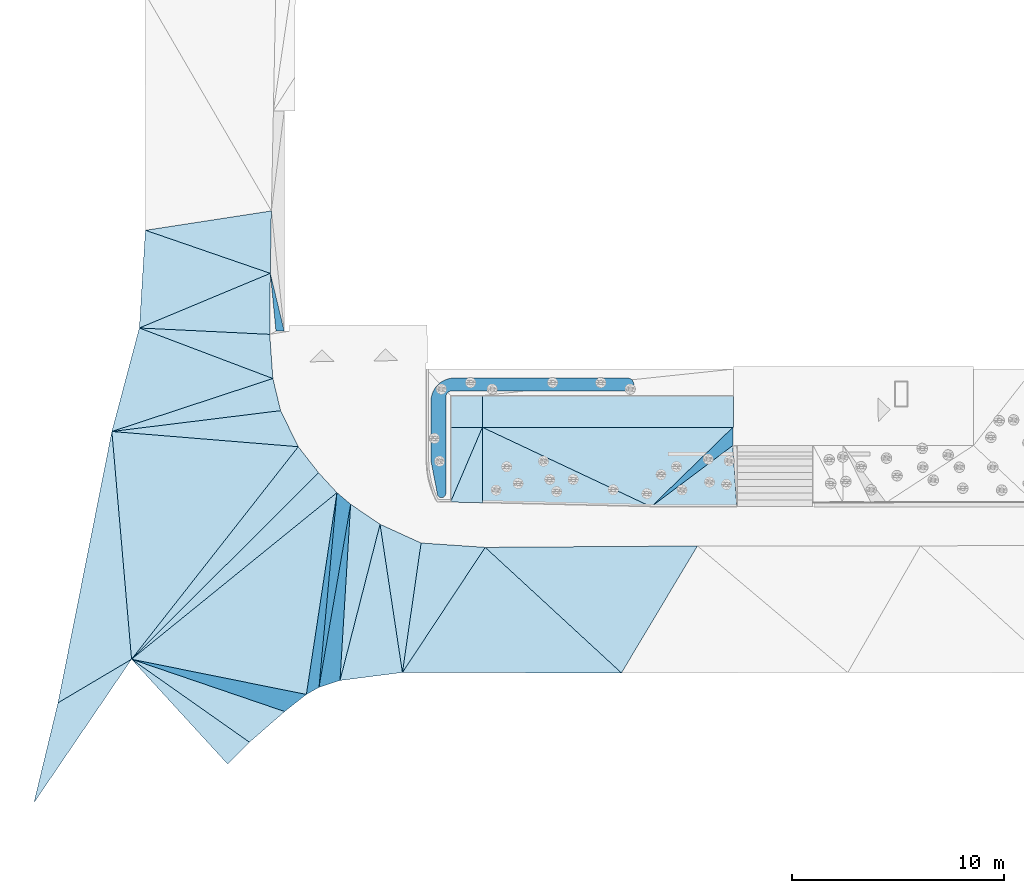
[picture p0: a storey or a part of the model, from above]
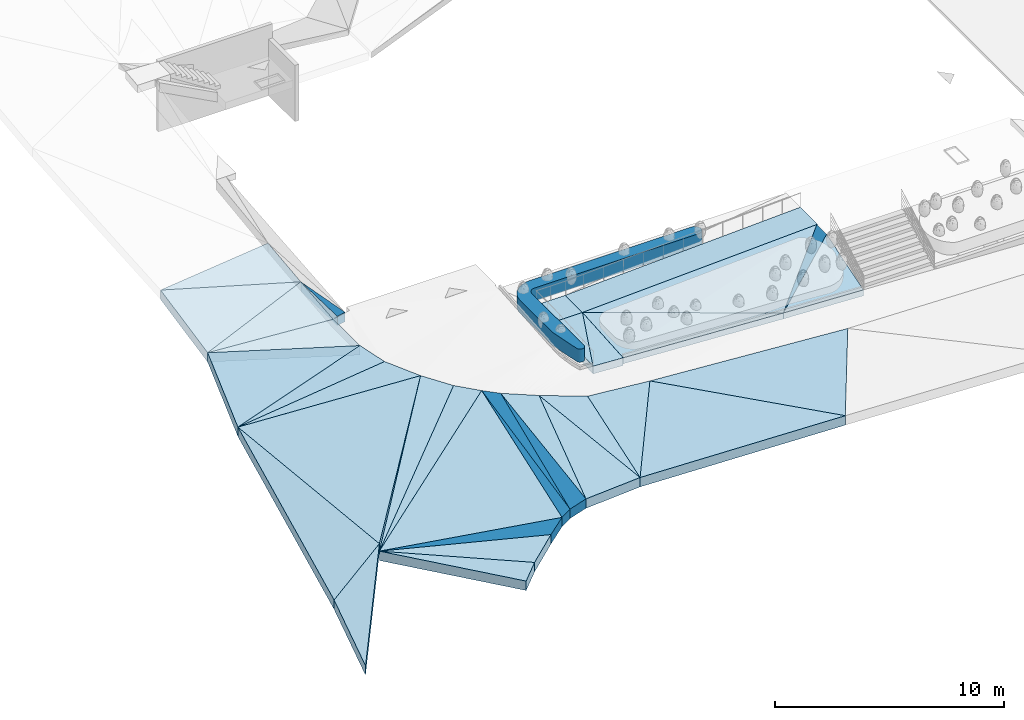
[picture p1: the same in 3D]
Properties of the parts of a building model (IFC2X3), part 1 of 2

# File
Description: ViewDefinition [CoordinationView_V2.0], RevitIdentifiers [ContentGUID: , VersionGUID: e908e2d4-4760-4d74-834a-3a2befb9f71d, NumberOfSaves: 164], ExchangeRequirement [], CoordinateReference [CoordinateBase: Project Base Point, ProjectSite: Internal]
File name: A246760_Ombygging av eksisterende legevakt_LARK.ifc
Time: 2025-12-17T15:13:17+01:00
Organization: Arkitema
Written by: ODA SDAI 22.12
Made in: Autodesk Revit 23.1.80.30 (ENU) - IFC 23.4.1.0

# IfcProject, A236760
LongName: TROMSØ LEGEVAKT; Phase: <Project Status>

# IfcSite, Default
RefLatitude: 59, 54, 57, 601318; RefLongitude: 10, 44, 59, 999999; RefElevation: 0 m

# IfcSite: Coordinate Marker Primary:Landscape Architect, Coordinate Marker Primary:Landscape Architect:896850
Material: A_Coordinate Marker_URB

# IfcBuilding, <Building Name>
LongName: <Building Name>
Pset_BuildingCommon - NumberOfStoreys: 1

# IfcBuildingStorey: Level:A_Level_Project Base Point, 00 - HAV
In: <Building Name>
LongName: 00 - HAV; Elevation: 0 m
Pset_AirSideSystemInformation - Name: 00 - HAV; sets with these values: 2

# IfcBuildingElementProxy: 011_Entrépil_3D:Hovedentré (6)
In: 00 - HAV
Type - Material: Entrépil
Pset_BuildingElementProxyCommon - Reference: Hovedentré; sets with these values: 2
Name (011_Entrépil_3D:Hovedentré:...)
1719524
1719576
1719661
1719735
1926711
1976187

# IfcBuildingElementProxy: 812_Shrub_Solitary:812xxx Amelanchier laevis (Allegheny serviceberry) (Multi-stem), 4m 2 (49)
In: 00 - HAV
Type - Material: <Unnamed>
Classification: 812 (Uniformat)
Pset_BuildingElementProxyCommon - Reference: 812xxx Amelanchier laevis (Allegheny serviceberry) (Multi-stem), 4m 2; sets with these values: 2
Name (812_Shrub_Solitary:812xxx Amelanchier laevis (Allegheny serviceberry) (Multi-stem), 4m 2:...)
1756752
1756895
1757022
1757053
1757088
1757123
1757158
1757193
1757228
1757263
1757323
1757370
1757407
1757446
1757481
1757514
1757553
1757588
1757623
1757658
1757697
1757736
1757783
1757818
1757865
1757928
1757989
1758052
1758127
1758190
1758253
1758316
1758377
1758440
1758503
1758564
1758690
1952593
1952684
1952703
1952741
1960945
1960970
1960990
1961012
1961034
1961054
1961074
1961094

# IfcBuildingElementProxy: rist:rist (3)
In: 00 - HAV
Type - Material: A_Default_Building_Component
Pset_BuildingElementProxyCommon - Reference: rist; sets with these values: 2
Name (rist:rist:...)
1971097
1971388
1971627

# IfcRailing: Railing:760 Kantstein 120x300mm (5)
In: 00 - HAV
Classification: 76 Veger og plasser (Uniformat)
Pset_QuantityTakeOff - Reference: 760 Kantstein 120x300mm
Pset_RailingCommon - IsExternal: no; Reference: 760 Kantstein 120x300mm; Height: 1.2 m
Name (Railing:760 Kantstein 120x300mm:...) | Material
1765355 | Site - Concrete - Curb
1765792 | Site - Concrete - Curb
1766145 | Site - Concrete - Curb, A_Default_Building_Part
1979676 | Site - Concrete - Curb
1979781 | Site - Concrete - Curb

# IfcRailing: Railing:800mm Pipe håndløper, Railing:800mm Pipe håndløper:1772769
In: 00 - HAV
Material: A_Finish_Metal_Steel_Brushed, Lys
Pset_QuantityTakeOff - Reference: 800mm Pipe håndløper
Pset_RailingCommon - IsExternal: no; Reference: 800mm Pipe håndløper; Height: 1.2192 m

# IfcRailing: Railing:900mm Pipe (2)
In: 00 - HAV
Material: A_Finish_Metal_Steel_Brushed, Lys
Pset_QuantityTakeOff - Reference: 900mm Pipe
Pset_RailingCommon - IsExternal: no; Reference: 900mm Pipe; Height: 1.2192 m
Name (Railing:900mm Pipe:...)
1718188
1718577

# IfcRoof: Basic Roof:772 Stauder, Geranium phaeum (Storkenæb Bølgekronede) (4)
In: 00 - HAV
Classification: 772 Beplantning (Uniformat); Material: Planting - Shrubs and hedges - Busker 0.7 m
Pset_QuantityTakeOff - Reference: 772 Stauder, Geranium phaeum (Storkenæb Bølgekronede)
Pset_RoofCommon - IsExternal: yes; Reference: 772 Stauder, Geranium phaeum (Storkenæb Bølgekronede)
Name (Basic Roof:772 Stauder, Geranium phaeum (Storkenæb Bølgekronede):...) | ProjectedArea (m2) | TotalArea (m2)
1930701 | 30.0611 | 30.9692
1931496 | 27.967 | 29.6557
1931990 | 4.85519 | 4.55826
1960116 | 8.22603 | 8.65733

# IfcSlab: Basic Roof:772 Stauder, Geranium phaeum (Storkenæb Bølgekronede) (2)
In: 00 - HAV
PredefinedType: ROOF; Classification: 772 Beplantning (Uniformat); Material: Planting - Shrubs and hedges - Busker 0.7 m
Pset_QuantityTakeOff - Reference: 772 Stauder, Geranium phaeum (Storkenæb Bølgekronede); sets with these values: 2
Pset_SlabCommon - IsExternal: yes; PitchAngle: 0 deg; Reference: 772 Stauder, Geranium phaeum (Storkenæb Bølgekronede)
Name (Basic Roof:772 Stauder, Geranium phaeum (Storkenæb Bølgekronede):...)
1931990
1960116

# IfcSlab: Floor:760 Grus, Floor:760 Grus:1980512
In: 00 - HAV
Type - PredefinedType: FLOOR
Classification: 76 Veger og plasser (Uniformat); Material: Site - Gravel - Steinmel, Site - Gravel - Stabilitet grus, Site - Gravel - Bunnsikringsgrus
Pset_QuantityTakeOff - Reference: 760 Grus; sets with these values: 2
Pset_SlabCommon - IsExternal: yes; LoadBearing: no; Reference: 760 Grus; PitchAngle: 27.9591 deg

# IfcSlab: Floor:761 Asfalt - Gangarealer (77)
In: 00 - HAV
Classification: 761 Veger (Uniformat)
Pset_QuantityTakeOff - Reference: 761 Asfalt - Gangarealer; sets with these values: 2
Pset_SlabCommon - IsExternal: yes; LoadBearing: no; Reference: 761 Asfalt - Gangarealer
Name (Floor:761 Asfalt - Gangarealer:...) | PitchAngle (deg) | Material
1763140 | 3.70708
3 x 1763140 | 3.70708 | Site - Aspahlt - Pulverasfalt 0.025 m, A_Default_Building_Part 0.05 m, Site - Gravel - Stabilitet grus 0.1 m, Site - Gravel - Bunnsikringsgrus 0.325 m
1763140 | 2.22173 | Site - Aspahlt - Pulverasfalt 0.025 m, A_Default_Building_Part 0.05 m, Site - Gravel - Stabilitet grus 0.1 m, Site - Gravel - Bunnsikringsgrus 0.325 m
1763140 | 1.93982 | Site - Aspahlt - Pulverasfalt 0.025 m, A_Default_Building_Part 0.05 m, Site - Gravel - Stabilitet grus 0.1 m, Site - Gravel - Bunnsikringsgrus 0.325 m
1763140 | 3.72437 | Site - Aspahlt - Pulverasfalt 0.025 m, A_Default_Building_Part 0.05 m, Site - Gravel - Stabilitet grus 0.1 m, Site - Gravel - Bunnsikringsgrus 0.325 m
1763140 | 0.475138 | Site - Aspahlt - Pulverasfalt 0.025 m, A_Default_Building_Part 0.05 m, Site - Gravel - Stabilitet grus 0.1 m, Site - Gravel - Bunnsikringsgrus 0.325 m
1763140 | 2.44105 | Site - Aspahlt - Pulverasfalt 0.025 m, A_Default_Building_Part 0.05 m, Site - Gravel - Stabilitet grus 0.1 m, Site - Gravel - Bunnsikringsgrus 0.325 m
1763140 | 3.73939 | Site - Aspahlt - Pulverasfalt 0.025 m, A_Default_Building_Part 0.05 m, Site - Gravel - Stabilitet grus 0.1 m, Site - Gravel - Bunnsikringsgrus 0.325 m
1763140 | 0.317033 | Site - Aspahlt - Pulverasfalt 0.025 m, A_Default_Building_Part 0.05 m, Site - Gravel - Stabilitet grus 0.1 m, Site - Gravel - Bunnsikringsgrus 0.325 m
1763140 | 0.778442 | Site - Aspahlt - Pulverasfalt 0.025 m, A_Default_Building_Part 0.05 m, Site - Gravel - Stabilitet grus 0.1 m, Site - Gravel - Bunnsikringsgrus 0.325 m
1763140 | 0.641729 | Site - Aspahlt - Pulverasfalt 0.025 m, A_Default_Building_Part 0.05 m, Site - Gravel - Stabilitet grus 0.1 m, Site - Gravel - Bunnsikringsgrus 0.325 m
1763140 | 2.55907 | Site - Aspahlt - Pulverasfalt 0.025 m, A_Default_Building_Part 0.05 m, Site - Gravel - Stabilitet grus 0.1 m, Site - Gravel - Bunnsikringsgrus 0.325 m
1763140 | 2.20551 | Site - Aspahlt - Pulverasfalt 0.025 m, A_Default_Building_Part 0.05 m, Site - Gravel - Stabilitet grus 0.1 m, Site - Gravel - Bunnsikringsgrus 0.325 m
1763140 | 1.61241 | Site - Aspahlt - Pulverasfalt 0.025 m, A_Default_Building_Part 0.05 m, Site - Gravel - Stabilitet grus 0.1 m, Site - Gravel - Bunnsikringsgrus 0.325 m
1763140 | 3.23586 | Site - Aspahlt - Pulverasfalt 0.025 m, A_Default_Building_Part 0.05 m, Site - Gravel - Stabilitet grus 0.1 m, Site - Gravel - Bunnsikringsgrus 0.325 m
1763140 | 2.4268 | Site - Aspahlt - Pulverasfalt 0.025 m, A_Default_Building_Part 0.05 m, Site - Gravel - Stabilitet grus 0.1 m, Site - Gravel - Bunnsikringsgrus 0.325 m
1763140 | 2.91863 | Site - Aspahlt - Pulverasfalt 0.025 m, A_Default_Building_Part 0.05 m, Site - Gravel - Stabilitet grus 0.1 m, Site - Gravel - Bunnsikringsgrus 0.325 m
1763140 | 3.35113 | Site - Aspahlt - Pulverasfalt 0.025 m, A_Default_Building_Part 0.05 m, Site - Gravel - Stabilitet grus 0.1 m, Site - Gravel - Bunnsikringsgrus 0.325 m
1763140 | 2.57261 | Site - Aspahlt - Pulverasfalt 0.025 m, A_Default_Building_Part 0.05 m, Site - Gravel - Stabilitet grus 0.1 m, Site - Gravel - Bunnsikringsgrus 0.325 m
1763140 | 2.5678 | Site - Aspahlt - Pulverasfalt 0.025 m, A_Default_Building_Part 0.05 m, Site - Gravel - Stabilitet grus 0.1 m, Site - Gravel - Bunnsikringsgrus 0.325 m
1763140 | 3.9037 | Site - Aspahlt - Pulverasfalt 0.025 m, A_Default_Building_Part 0.05 m, Site - Gravel - Stabilitet grus 0.1 m, Site - Gravel - Bunnsikringsgrus 0.325 m
1763140 | 2.61773 | Site - Aspahlt - Pulverasfalt 0.025 m, A_Default_Building_Part 0.05 m, Site - Gravel - Stabilitet grus 0.1 m, Site - Gravel - Bunnsikringsgrus 0.325 m
1763140 | 1.37486 | Site - Aspahlt - Pulverasfalt 0.025 m, A_Default_Building_Part 0.05 m, Site - Gravel - Stabilitet grus 0.1 m, Site - Gravel - Bunnsikringsgrus 0.325 m
1763140 | 4.61341 | Site - Aspahlt - Pulverasfalt 0.025 m, A_Default_Building_Part 0.05 m, Site - Gravel - Stabilitet grus 0.1 m, Site - Gravel - Bunnsikringsgrus 0.325 m
1763140 | 5.71507 | Site - Aspahlt - Pulverasfalt 0.025 m, A_Default_Building_Part 0.05 m, Site - Gravel - Stabilitet grus 0.1 m, Site - Gravel - Bunnsikringsgrus 0.325 m
1763140 | 5.27475 | Site - Aspahlt - Pulverasfalt 0.025 m, A_Default_Building_Part 0.05 m, Site - Gravel - Stabilitet grus 0.1 m, Site - Gravel - Bunnsikringsgrus 0.325 m
1763140 | 4.27942 | Site - Aspahlt - Pulverasfalt 0.025 m, A_Default_Building_Part 0.05 m, Site - Gravel - Stabilitet grus 0.1 m, Site - Gravel - Bunnsikringsgrus 0.325 m
1763140 | 3.64257 | Site - Aspahlt - Pulverasfalt 0.025 m, A_Default_Building_Part 0.05 m, Site - Gravel - Stabilitet grus 0.1 m, Site - Gravel - Bunnsikringsgrus 0.325 m
1763140 | 3.82142 | Site - Aspahlt - Pulverasfalt 0.025 m, A_Default_Building_Part 0.05 m, Site - Gravel - Stabilitet grus 0.1 m, Site - Gravel - Bunnsikringsgrus 0.325 m
1763140 | 3.6637 | Site - Aspahlt - Pulverasfalt 0.025 m, A_Default_Building_Part 0.05 m, Site - Gravel - Stabilitet grus 0.1 m, Site - Gravel - Bunnsikringsgrus 0.325 m
1763140 | 5.95443 | Site - Aspahlt - Pulverasfalt 0.025 m, A_Default_Building_Part 0.05 m, Site - Gravel - Stabilitet grus 0.1 m, Site - Gravel - Bunnsikringsgrus 0.325 m
1763140 | 5.04573 | Site - Aspahlt - Pulverasfalt 0.025 m, A_Default_Building_Part 0.05 m, Site - Gravel - Stabilitet grus 0.1 m, Site - Gravel - Bunnsikringsgrus 0.325 m
1763140 | 3.60639 | Site - Aspahlt - Pulverasfalt 0.025 m, A_Default_Building_Part 0.05 m, Site - Gravel - Stabilitet grus 0.1 m, Site - Gravel - Bunnsikringsgrus 0.325 m
1763140 | 5.08046 | Site - Aspahlt - Pulverasfalt 0.025 m, A_Default_Building_Part 0.05 m, Site - Gravel - Stabilitet grus 0.1 m, Site - Gravel - Bunnsikringsgrus 0.325 m
1763140 | 4.43556 | Site - Aspahlt - Pulverasfalt 0.025 m, A_Default_Building_Part 0.05 m, Site - Gravel - Stabilitet grus 0.1 m, Site - Gravel - Bunnsikringsgrus 0.325 m
1763140 | 3.49331 | Site - Aspahlt - Pulverasfalt 0.025 m, A_Default_Building_Part 0.05 m, Site - Gravel - Stabilitet grus 0.1 m, Site - Gravel - Bunnsikringsgrus 0.325 m
1763140 | 2.78615 | Site - Aspahlt - Pulverasfalt 0.025 m, A_Default_Building_Part 0.05 m, Site - Gravel - Stabilitet grus 0.1 m, Site - Gravel - Bunnsikringsgrus 0.325 m
1763140 | 6.29455 | Site - Aspahlt - Pulverasfalt 0.025 m, A_Default_Building_Part 0.05 m, Site - Gravel - Stabilitet grus 0.1 m, Site - Gravel - Bunnsikringsgrus 0.325 m
1763140 | 4.63635 | Site - Aspahlt - Pulverasfalt 0.025 m, A_Default_Building_Part 0.05 m, Site - Gravel - Stabilitet grus 0.1 m, Site - Gravel - Bunnsikringsgrus 0.325 m
1763140 | 5.64824 | Site - Aspahlt - Pulverasfalt 0.025 m, A_Default_Building_Part 0.05 m, Site - Gravel - Stabilitet grus 0.1 m, Site - Gravel - Bunnsikringsgrus 0.325 m
1763140 | 5.82056 | Site - Aspahlt - Pulverasfalt 0.025 m, A_Default_Building_Part 0.05 m, Site - Gravel - Stabilitet grus 0.1 m, Site - Gravel - Bunnsikringsgrus 0.325 m
1763140 | 4.03826 | Site - Aspahlt - Pulverasfalt 0.025 m, A_Default_Building_Part 0.05 m, Site - Gravel - Stabilitet grus 0.1 m, Site - Gravel - Bunnsikringsgrus 0.325 m
1763140 | 5.35696 | Site - Aspahlt - Pulverasfalt 0.025 m, A_Default_Building_Part 0.05 m, Site - Gravel - Stabilitet grus 0.1 m, Site - Gravel - Bunnsikringsgrus 0.325 m
1763140 | 4.81885 | Site - Aspahlt - Pulverasfalt 0.025 m, A_Default_Building_Part 0.05 m, Site - Gravel - Stabilitet grus 0.1 m, Site - Gravel - Bunnsikringsgrus 0.325 m
1763140 | 7.19982 | Site - Aspahlt - Pulverasfalt 0.025 m, A_Default_Building_Part 0.05 m, Site - Gravel - Stabilitet grus 0.1 m, Site - Gravel - Bunnsikringsgrus 0.325 m
1763140 | 8.5294 | Site - Aspahlt - Pulverasfalt 0.025 m, A_Default_Building_Part 0.05 m, Site - Gravel - Stabilitet grus 0.1 m, Site - Gravel - Bunnsikringsgrus 0.325 m
1763140 | 4.6075 | Site - Aspahlt - Pulverasfalt 0.025 m, A_Default_Building_Part 0.05 m, Site - Gravel - Stabilitet grus 0.1 m, Site - Gravel - Bunnsikringsgrus 0.325 m
1763140 | 4.09251 | Site - Aspahlt - Pulverasfalt 0.025 m, A_Default_Building_Part 0.05 m, Site - Gravel - Stabilitet grus 0.1 m, Site - Gravel - Bunnsikringsgrus 0.325 m
1763140 | 5.78706 | Site - Aspahlt - Pulverasfalt 0.025 m, A_Default_Building_Part 0.05 m, Site - Gravel - Stabilitet grus 0.1 m, Site - Gravel - Bunnsikringsgrus 0.325 m
1763140 | 4.57586 | Site - Aspahlt - Pulverasfalt 0.025 m, A_Default_Building_Part 0.05 m, Site - Gravel - Stabilitet grus 0.1 m, Site - Gravel - Bunnsikringsgrus 0.325 m
1763140 | 6.2257 | Site - Aspahlt - Pulverasfalt 0.025 m, A_Default_Building_Part 0.05 m, Site - Gravel - Stabilitet grus 0.1 m, Site - Gravel - Bunnsikringsgrus 0.325 m
1763140 | 4.58543 | Site - Aspahlt - Pulverasfalt 0.025 m, A_Default_Building_Part 0.05 m, Site - Gravel - Stabilitet grus 0.1 m, Site - Gravel - Bunnsikringsgrus 0.325 m
1763140 | 4.86651 | Site - Aspahlt - Pulverasfalt 0.025 m, A_Default_Building_Part 0.05 m, Site - Gravel - Stabilitet grus 0.1 m, Site - Gravel - Bunnsikringsgrus 0.325 m
1763140 | 5.05189 | Site - Aspahlt - Pulverasfalt 0.025 m, A_Default_Building_Part 0.05 m, Site - Gravel - Stabilitet grus 0.1 m, Site - Gravel - Bunnsikringsgrus 0.325 m
1763140 | 3.75882 | Site - Aspahlt - Pulverasfalt 0.025 m, A_Default_Building_Part 0.05 m, Site - Gravel - Stabilitet grus 0.1 m, Site - Gravel - Bunnsikringsgrus 0.325 m
1763140 | 4.20286 | Site - Aspahlt - Pulverasfalt 0.025 m, A_Default_Building_Part 0.05 m, Site - Gravel - Stabilitet grus 0.1 m, Site - Gravel - Bunnsikringsgrus 0.325 m
1763140 | 3.16884 | Site - Aspahlt - Pulverasfalt 0.025 m, A_Default_Building_Part 0.05 m, Site - Gravel - Stabilitet grus 0.1 m, Site - Gravel - Bunnsikringsgrus 0.325 m
1763140 | 2.95884 | Site - Aspahlt - Pulverasfalt 0.025 m, A_Default_Building_Part 0.05 m, Site - Gravel - Stabilitet grus 0.1 m, Site - Gravel - Bunnsikringsgrus 0.325 m
1763140 | 3.29438 | Site - Aspahlt - Pulverasfalt 0.025 m, A_Default_Building_Part 0.05 m, Site - Gravel - Stabilitet grus 0.1 m, Site - Gravel - Bunnsikringsgrus 0.325 m
1763140 | 2.33751 | Site - Aspahlt - Pulverasfalt 0.025 m, A_Default_Building_Part 0.05 m, Site - Gravel - Stabilitet grus 0.1 m, Site - Gravel - Bunnsikringsgrus 0.325 m
1763140 | 5.18628 | Site - Aspahlt - Pulverasfalt 0.025 m, A_Default_Building_Part 0.05 m, Site - Gravel - Stabilitet grus 0.1 m, Site - Gravel - Bunnsikringsgrus 0.325 m
1763140 | 3.3745 | Site - Aspahlt - Pulverasfalt 0.025 m, A_Default_Building_Part 0.05 m, Site - Gravel - Stabilitet grus 0.1 m, Site - Gravel - Bunnsikringsgrus 0.325 m
1763140 | 3.503 | Site - Aspahlt - Pulverasfalt 0.025 m, A_Default_Building_Part 0.05 m, Site - Gravel - Stabilitet grus 0.1 m, Site - Gravel - Bunnsikringsgrus 0.325 m
1763140 | 3.41036 | Site - Aspahlt - Pulverasfalt 0.025 m, A_Default_Building_Part 0.05 m, Site - Gravel - Stabilitet grus 0.1 m, Site - Gravel - Bunnsikringsgrus 0.325 m
1763140 | 2.08241 | Site - Aspahlt - Pulverasfalt 0.025 m, A_Default_Building_Part 0.05 m, Site - Gravel - Stabilitet grus 0.1 m, Site - Gravel - Bunnsikringsgrus 0.325 m
1763140 | 4.00822 | Site - Aspahlt - Pulverasfalt 0.025 m, A_Default_Building_Part 0.05 m, Site - Gravel - Stabilitet grus 0.1 m, Site - Gravel - Bunnsikringsgrus 0.325 m
1763140 | 3.59995 | Site - Aspahlt - Pulverasfalt 0.025 m, A_Default_Building_Part 0.05 m, Site - Gravel - Stabilitet grus 0.1 m, Site - Gravel - Bunnsikringsgrus 0.325 m
1763140 | 5.02019 | Site - Aspahlt - Pulverasfalt 0.025 m, A_Default_Building_Part 0.05 m, Site - Gravel - Stabilitet grus 0.1 m, Site - Gravel - Bunnsikringsgrus 0.325 m
1763140 | 9.12842 | Site - Aspahlt - Pulverasfalt 0.025 m, A_Default_Building_Part 0.05 m, Site - Gravel - Stabilitet grus 0.1 m, Site - Gravel - Bunnsikringsgrus 0.325 m
1926366 | 7.31267
1926366 | 14.4353 | Site - Aspahlt - Pulverasfalt 0.025 m, A_Default_Building_Part 0.05 m, Site - Gravel - Stabilitet grus 0.1 m, Site - Gravel - Bunnsikringsgrus 0.325 m
1926366 | 0.43844 | Site - Aspahlt - Pulverasfalt 0.025 m, A_Default_Building_Part 0.05 m, Site - Gravel - Stabilitet grus 0.1 m, Site - Gravel - Bunnsikringsgrus 0.325 m
1926366 | 7.31267 | Site - Aspahlt - Pulverasfalt 0.025 m, A_Default_Building_Part 0.05 m, Site - Gravel - Stabilitet grus 0.1 m, Site - Gravel - Bunnsikringsgrus 0.325 m
1926366 | 7.68545 | Site - Aspahlt - Pulverasfalt 0.025 m, A_Default_Building_Part 0.05 m, Site - Gravel - Stabilitet grus 0.1 m, Site - Gravel - Bunnsikringsgrus 0.325 m
1926366 | 53.5615 | Site - Aspahlt - Pulverasfalt 0.025 m, A_Default_Building_Part 0.05 m, Site - Gravel - Stabilitet grus 0.1 m, Site - Gravel - Bunnsikringsgrus 0.325 m

# IfcSlab: Floor:761 Asfalt - Gangarealer, Floor:761 Asfalt - Gangarealer:1696856
In: 00 - HAV
Type - PredefinedType: FLOOR
Classification: 761 Veger (Uniformat); Material: Site - Aspahlt - Pulverasfalt, A_Default_Building_Part, Site - Gravel - Stabilitet grus, Site - Gravel - Bunnsikringsgrus
Pset_QuantityTakeOff - Reference: 761 Asfalt - Gangarealer; sets with these values: 2
Pset_SlabCommon - IsExternal: yes; LoadBearing: no; Reference: 761 Asfalt - Gangarealer; PitchAngle: 4.01153 deg

# IfcSlab: Floor:761 Asfalt - Kjørearealer (136)
In: 00 - HAV
Classification: 761 Veger (Uniformat)
Pset_QuantityTakeOff - Reference: 761 Asfalt - Kjørearealer; sets with these values: 2
Pset_SlabCommon - IsExternal: yes; LoadBearing: no; Reference: 761 Asfalt - Kjørearealer
Name (Floor:761 Asfalt - Kjørearealer:...) | PitchAngle (deg) | Material
1694630 | 4.053
1694630 | 4.18855 | Site - Asphalt - Asfaltbetong 0.03 m, A_Default_Building_Part 0.07 m, Site - Gravel - Stabilitet grus 0.2 m, Site - Gravel - Bunnsikringsgrus 0.2 m
1694630 | 5.41156 | Site - Asphalt - Asfaltbetong 0.03 m, A_Default_Building_Part 0.07 m, Site - Gravel - Stabilitet grus 0.2 m, Site - Gravel - Bunnsikringsgrus 0.2 m
1694630 | 4.05574 | Site - Asphalt - Asfaltbetong 0.03 m, A_Default_Building_Part 0.07 m, Site - Gravel - Stabilitet grus 0.2 m, Site - Gravel - Bunnsikringsgrus 0.2 m
1694630 | 3.89272 | Site - Asphalt - Asfaltbetong 0.03 m, A_Default_Building_Part 0.07 m, Site - Gravel - Stabilitet grus 0.2 m, Site - Gravel - Bunnsikringsgrus 0.2 m
1694630 | 4.053 | Site - Asphalt - Asfaltbetong 0.03 m, A_Default_Building_Part 0.07 m, Site - Gravel - Stabilitet grus 0.2 m, Site - Gravel - Bunnsikringsgrus 0.2 m
1694630 | 1.34318 | Site - Asphalt - Asfaltbetong 0.03 m, A_Default_Building_Part 0.07 m, Site - Gravel - Stabilitet grus 0.2 m, Site - Gravel - Bunnsikringsgrus 0.2 m
1694630 | 4.65396 | Site - Asphalt - Asfaltbetong 0.03 m, A_Default_Building_Part 0.07 m, Site - Gravel - Stabilitet grus 0.2 m, Site - Gravel - Bunnsikringsgrus 0.2 m
1694630 | 4.51738 | Site - Asphalt - Asfaltbetong 0.03 m, A_Default_Building_Part 0.07 m, Site - Gravel - Stabilitet grus 0.2 m, Site - Gravel - Bunnsikringsgrus 0.2 m
1694630 | 3.10957 | Site - Asphalt - Asfaltbetong 0.03 m, A_Default_Building_Part 0.07 m, Site - Gravel - Stabilitet grus 0.2 m, Site - Gravel - Bunnsikringsgrus 0.2 m
1694630 | 4.57001 | Site - Asphalt - Asfaltbetong 0.03 m, A_Default_Building_Part 0.07 m, Site - Gravel - Stabilitet grus 0.2 m, Site - Gravel - Bunnsikringsgrus 0.2 m
1694630 | 4.54245 | Site - Asphalt - Asfaltbetong 0.03 m, A_Default_Building_Part 0.07 m, Site - Gravel - Stabilitet grus 0.2 m, Site - Gravel - Bunnsikringsgrus 0.2 m
1694630 | 5.5919 | Site - Asphalt - Asfaltbetong 0.03 m, A_Default_Building_Part 0.07 m, Site - Gravel - Stabilitet grus 0.2 m, Site - Gravel - Bunnsikringsgrus 0.2 m
1698117 | 2.88625
1698117 | 4.18229 | Site - Asphalt - Asfaltbetong 0.03 m, A_Default_Building_Part 0.07 m, Site - Gravel - Stabilitet grus 0.2 m, Site - Gravel - Bunnsikringsgrus 0.2 m
1698117 | 3.70061 | Site - Asphalt - Asfaltbetong 0.03 m, A_Default_Building_Part 0.07 m, Site - Gravel - Stabilitet grus 0.2 m, Site - Gravel - Bunnsikringsgrus 0.2 m
1698117 | 2.53295 | Site - Asphalt - Asfaltbetong 0.03 m, A_Default_Building_Part 0.07 m, Site - Gravel - Stabilitet grus 0.2 m, Site - Gravel - Bunnsikringsgrus 0.2 m
1698117 | 3.17414 | Site - Asphalt - Asfaltbetong 0.03 m, A_Default_Building_Part 0.07 m, Site - Gravel - Stabilitet grus 0.2 m, Site - Gravel - Bunnsikringsgrus 0.2 m
1698117 | 4.54877 | Site - Asphalt - Asfaltbetong 0.03 m, A_Default_Building_Part 0.07 m, Site - Gravel - Stabilitet grus 0.2 m, Site - Gravel - Bunnsikringsgrus 0.2 m
1698117 | 3.57814 | Site - Asphalt - Asfaltbetong 0.03 m, A_Default_Building_Part 0.07 m, Site - Gravel - Stabilitet grus 0.2 m, Site - Gravel - Bunnsikringsgrus 0.2 m
1698117 | 3.29554 | Site - Asphalt - Asfaltbetong 0.03 m, A_Default_Building_Part 0.07 m, Site - Gravel - Stabilitet grus 0.2 m, Site - Gravel - Bunnsikringsgrus 0.2 m
1698117 | 2.67689 | Site - Asphalt - Asfaltbetong 0.03 m, A_Default_Building_Part 0.07 m, Site - Gravel - Stabilitet grus 0.2 m, Site - Gravel - Bunnsikringsgrus 0.2 m
1698117 | 2.77881 | Site - Asphalt - Asfaltbetong 0.03 m, A_Default_Building_Part 0.07 m, Site - Gravel - Stabilitet grus 0.2 m, Site - Gravel - Bunnsikringsgrus 0.2 m
1698117 | 2.68364 | Site - Asphalt - Asfaltbetong 0.03 m, A_Default_Building_Part 0.07 m, Site - Gravel - Stabilitet grus 0.2 m, Site - Gravel - Bunnsikringsgrus 0.2 m
1698117 | 2.18274 | Site - Asphalt - Asfaltbetong 0.03 m, A_Default_Building_Part 0.07 m, Site - Gravel - Stabilitet grus 0.2 m, Site - Gravel - Bunnsikringsgrus 0.2 m
1698117 | 2.07092 | Site - Asphalt - Asfaltbetong 0.03 m, A_Default_Building_Part 0.07 m, Site - Gravel - Stabilitet grus 0.2 m, Site - Gravel - Bunnsikringsgrus 0.2 m
1698117 | 4.85182 | Site - Asphalt - Asfaltbetong 0.03 m, A_Default_Building_Part 0.07 m, Site - Gravel - Stabilitet grus 0.2 m, Site - Gravel - Bunnsikringsgrus 0.2 m
1698117 | 2.35265 | Site - Asphalt - Asfaltbetong 0.03 m, A_Default_Building_Part 0.07 m, Site - Gravel - Stabilitet grus 0.2 m, Site - Gravel - Bunnsikringsgrus 0.2 m
1698117 | 1.88367 | Site - Asphalt - Asfaltbetong 0.03 m, A_Default_Building_Part 0.07 m, Site - Gravel - Stabilitet grus 0.2 m, Site - Gravel - Bunnsikringsgrus 0.2 m
1698117 | 2.3319 | Site - Asphalt - Asfaltbetong 0.03 m, A_Default_Building_Part 0.07 m, Site - Gravel - Stabilitet grus 0.2 m, Site - Gravel - Bunnsikringsgrus 0.2 m
1698117 | 2.16329 | Site - Asphalt - Asfaltbetong 0.03 m, A_Default_Building_Part 0.07 m, Site - Gravel - Stabilitet grus 0.2 m, Site - Gravel - Bunnsikringsgrus 0.2 m
1698117 | 2.99186 | Site - Asphalt - Asfaltbetong 0.03 m, A_Default_Building_Part 0.07 m, Site - Gravel - Stabilitet grus 0.2 m, Site - Gravel - Bunnsikringsgrus 0.2 m
1698117 | 2.98026 | Site - Asphalt - Asfaltbetong 0.03 m, A_Default_Building_Part 0.07 m, Site - Gravel - Stabilitet grus 0.2 m, Site - Gravel - Bunnsikringsgrus 0.2 m
1698117 | 3.32911 | Site - Asphalt - Asfaltbetong 0.03 m, A_Default_Building_Part 0.07 m, Site - Gravel - Stabilitet grus 0.2 m, Site - Gravel - Bunnsikringsgrus 0.2 m
1698117 | 3.00803 | Site - Asphalt - Asfaltbetong 0.03 m, A_Default_Building_Part 0.07 m, Site - Gravel - Stabilitet grus 0.2 m, Site - Gravel - Bunnsikringsgrus 0.2 m
1698117 | 2.4685 | Site - Asphalt - Asfaltbetong 0.03 m, A_Default_Building_Part 0.07 m, Site - Gravel - Stabilitet grus 0.2 m, Site - Gravel - Bunnsikringsgrus 0.2 m
1698117 | 3.33381 | Site - Asphalt - Asfaltbetong 0.03 m, A_Default_Building_Part 0.07 m, Site - Gravel - Stabilitet grus 0.2 m, Site - Gravel - Bunnsikringsgrus 0.2 m
1698117 | 1.4765 | Site - Asphalt - Asfaltbetong 0.03 m, A_Default_Building_Part 0.07 m, Site - Gravel - Stabilitet grus 0.2 m, Site - Gravel - Bunnsikringsgrus 0.2 m
1698117 | 2.74195 | Site - Asphalt - Asfaltbetong 0.03 m, A_Default_Building_Part 0.07 m, Site - Gravel - Stabilitet grus 0.2 m, Site - Gravel - Bunnsikringsgrus 0.2 m
1698117 | 4.29906 | Site - Asphalt - Asfaltbetong 0.03 m, A_Default_Building_Part 0.07 m, Site - Gravel - Stabilitet grus 0.2 m, Site - Gravel - Bunnsikringsgrus 0.2 m
1698117 | 2.40828 | Site - Asphalt - Asfaltbetong 0.03 m, A_Default_Building_Part 0.07 m, Site - Gravel - Stabilitet grus 0.2 m, Site - Gravel - Bunnsikringsgrus 0.2 m
1698117 | 3.87961 | Site - Asphalt - Asfaltbetong 0.03 m, A_Default_Building_Part 0.07 m, Site - Gravel - Stabilitet grus 0.2 m, Site - Gravel - Bunnsikringsgrus 0.2 m
1698117 | 3.51844 | Site - Asphalt - Asfaltbetong 0.03 m, A_Default_Building_Part 0.07 m, Site - Gravel - Stabilitet grus 0.2 m, Site - Gravel - Bunnsikringsgrus 0.2 m
1698117 | 5.12194 | Site - Asphalt - Asfaltbetong 0.03 m, A_Default_Building_Part 0.07 m, Site - Gravel - Stabilitet grus 0.2 m, Site - Gravel - Bunnsikringsgrus 0.2 m
1698117 | 2.8627 | Site - Asphalt - Asfaltbetong 0.03 m, A_Default_Building_Part 0.07 m, Site - Gravel - Stabilitet grus 0.2 m, Site - Gravel - Bunnsikringsgrus 0.2 m
1698117 | 4.61764 | Site - Asphalt - Asfaltbetong 0.03 m, A_Default_Building_Part 0.07 m, Site - Gravel - Stabilitet grus 0.2 m, Site - Gravel - Bunnsikringsgrus 0.2 m
1698117 | 3.10761 | Site - Asphalt - Asfaltbetong 0.03 m, A_Default_Building_Part 0.07 m, Site - Gravel - Stabilitet grus 0.2 m, Site - Gravel - Bunnsikringsgrus 0.2 m
1698117 | 3.03276 | Site - Asphalt - Asfaltbetong 0.03 m, A_Default_Building_Part 0.07 m, Site - Gravel - Stabilitet grus 0.2 m, Site - Gravel - Bunnsikringsgrus 0.2 m
1698117 | 1.84227 | Site - Asphalt - Asfaltbetong 0.03 m, A_Default_Building_Part 0.07 m, Site - Gravel - Stabilitet grus 0.2 m, Site - Gravel - Bunnsikringsgrus 0.2 m
1698117 | 2.88625 | Site - Asphalt - Asfaltbetong 0.03 m, A_Default_Building_Part 0.07 m, Site - Gravel - Stabilitet grus 0.2 m, Site - Gravel - Bunnsikringsgrus 0.2 m
1698117 | 3.01755 | Site - Asphalt - Asfaltbetong 0.03 m, A_Default_Building_Part 0.07 m, Site - Gravel - Stabilitet grus 0.2 m, Site - Gravel - Bunnsikringsgrus 0.2 m
1698117 | 4.61571 | Site - Asphalt - Asfaltbetong 0.03 m, A_Default_Building_Part 0.07 m, Site - Gravel - Stabilitet grus 0.2 m, Site - Gravel - Bunnsikringsgrus 0.2 m
1698117 | 1.54169 | Site - Asphalt - Asfaltbetong 0.03 m, A_Default_Building_Part 0.07 m, Site - Gravel - Stabilitet grus 0.2 m, Site - Gravel - Bunnsikringsgrus 0.2 m
1698117 | 1.79863 | Site - Asphalt - Asfaltbetong 0.03 m, A_Default_Building_Part 0.07 m, Site - Gravel - Stabilitet grus 0.2 m, Site - Gravel - Bunnsikringsgrus 0.2 m
1698117 | 4.53994 | Site - Asphalt - Asfaltbetong 0.03 m, A_Default_Building_Part 0.07 m, Site - Gravel - Stabilitet grus 0.2 m, Site - Gravel - Bunnsikringsgrus 0.2 m
1698301 | 3.13272
1698301 | 2.93232 | Site - Asphalt - Asfaltbetong 0.03 m, A_Default_Building_Part 0.07 m, Site - Gravel - Stabilitet grus 0.2 m, Site - Gravel - Bunnsikringsgrus 0.2 m
1698301 | 2.57739 | Site - Asphalt - Asfaltbetong 0.03 m, A_Default_Building_Part 0.07 m, Site - Gravel - Stabilitet grus 0.2 m, Site - Gravel - Bunnsikringsgrus 0.2 m
1698301 | 3.03418 | Site - Asphalt - Asfaltbetong 0.03 m, A_Default_Building_Part 0.07 m, Site - Gravel - Stabilitet grus 0.2 m, Site - Gravel - Bunnsikringsgrus 0.2 m
1698301 | 3.81279 | Site - Asphalt - Asfaltbetong 0.03 m, A_Default_Building_Part 0.07 m, Site - Gravel - Stabilitet grus 0.2 m, Site - Gravel - Bunnsikringsgrus 0.2 m
1698301 | 2.8483 | Site - Asphalt - Asfaltbetong 0.03 m, A_Default_Building_Part 0.07 m, Site - Gravel - Stabilitet grus 0.2 m, Site - Gravel - Bunnsikringsgrus 0.2 m
1698301 | 3.63613 | Site - Asphalt - Asfaltbetong 0.03 m, A_Default_Building_Part 0.07 m, Site - Gravel - Stabilitet grus 0.2 m, Site - Gravel - Bunnsikringsgrus 0.2 m
1698301 | 5.91456 | Site - Asphalt - Asfaltbetong 0.03 m, A_Default_Building_Part 0.07 m, Site - Gravel - Stabilitet grus 0.2 m, Site - Gravel - Bunnsikringsgrus 0.2 m
1698301 | 3.44815 | Site - Asphalt - Asfaltbetong 0.03 m, A_Default_Building_Part 0.07 m, Site - Gravel - Stabilitet grus 0.2 m, Site - Gravel - Bunnsikringsgrus 0.2 m
1698301 | 5.73988 | Site - Asphalt - Asfaltbetong 0.03 m, A_Default_Building_Part 0.07 m, Site - Gravel - Stabilitet grus 0.2 m, Site - Gravel - Bunnsikringsgrus 0.2 m
1698301 | 6.05419 | Site - Asphalt - Asfaltbetong 0.03 m, A_Default_Building_Part 0.07 m, Site - Gravel - Stabilitet grus 0.2 m, Site - Gravel - Bunnsikringsgrus 0.2 m
1698301 | 4.5628 | Site - Asphalt - Asfaltbetong 0.03 m, A_Default_Building_Part 0.07 m, Site - Gravel - Stabilitet grus 0.2 m, Site - Gravel - Bunnsikringsgrus 0.2 m
1698301 | 5.5514 | Site - Asphalt - Asfaltbetong 0.03 m, A_Default_Building_Part 0.07 m, Site - Gravel - Stabilitet grus 0.2 m, Site - Gravel - Bunnsikringsgrus 0.2 m
1698301 | 5.87515 | Site - Asphalt - Asfaltbetong 0.03 m, A_Default_Building_Part 0.07 m, Site - Gravel - Stabilitet grus 0.2 m, Site - Gravel - Bunnsikringsgrus 0.2 m
1698301 | 5.4714 | Site - Asphalt - Asfaltbetong 0.03 m, A_Default_Building_Part 0.07 m, Site - Gravel - Stabilitet grus 0.2 m, Site - Gravel - Bunnsikringsgrus 0.2 m
1698301 | 6.73841 | Site - Asphalt - Asfaltbetong 0.03 m, A_Default_Building_Part 0.07 m, Site - Gravel - Stabilitet grus 0.2 m, Site - Gravel - Bunnsikringsgrus 0.2 m
1698301 | 5.328 | Site - Asphalt - Asfaltbetong 0.03 m, A_Default_Building_Part 0.07 m, Site - Gravel - Stabilitet grus 0.2 m, Site - Gravel - Bunnsikringsgrus 0.2 m
1698301 | 5.02636 | Site - Asphalt - Asfaltbetong 0.03 m, A_Default_Building_Part 0.07 m, Site - Gravel - Stabilitet grus 0.2 m, Site - Gravel - Bunnsikringsgrus 0.2 m
1698301 | 8.35535 | Site - Asphalt - Asfaltbetong 0.03 m, A_Default_Building_Part 0.07 m, Site - Gravel - Stabilitet grus 0.2 m, Site - Gravel - Bunnsikringsgrus 0.2 m
1698301 | 0.691544 | Site - Asphalt - Asfaltbetong 0.03 m, A_Default_Building_Part 0.07 m, Site - Gravel - Stabilitet grus 0.2 m, Site - Gravel - Bunnsikringsgrus 0.2 m
1698301 | 0.98406 | Site - Asphalt - Asfaltbetong 0.03 m, A_Default_Building_Part 0.07 m, Site - Gravel - Stabilitet grus 0.2 m, Site - Gravel - Bunnsikringsgrus 0.2 m
1698301 | 2.44228 | Site - Asphalt - Asfaltbetong 0.03 m, A_Default_Building_Part 0.07 m, Site - Gravel - Stabilitet grus 0.2 m, Site - Gravel - Bunnsikringsgrus 0.2 m
1698301 | 8.2597 | Site - Asphalt - Asfaltbetong 0.03 m, A_Default_Building_Part 0.07 m, Site - Gravel - Stabilitet grus 0.2 m, Site - Gravel - Bunnsikringsgrus 0.2 m
1698301 | 2.78262 | Site - Asphalt - Asfaltbetong 0.03 m, A_Default_Building_Part 0.07 m, Site - Gravel - Stabilitet grus 0.2 m, Site - Gravel - Bunnsikringsgrus 0.2 m
1698301 | 3.03727 | Site - Asphalt - Asfaltbetong 0.03 m, A_Default_Building_Part 0.07 m, Site - Gravel - Stabilitet grus 0.2 m, Site - Gravel - Bunnsikringsgrus 0.2 m
1698301 | 3.35179 | Site - Asphalt - Asfaltbetong 0.03 m, A_Default_Building_Part 0.07 m, Site - Gravel - Stabilitet grus 0.2 m, Site - Gravel - Bunnsikringsgrus 0.2 m
1698301 | 4.57626 | Site - Asphalt - Asfaltbetong 0.03 m, A_Default_Building_Part 0.07 m, Site - Gravel - Stabilitet grus 0.2 m, Site - Gravel - Bunnsikringsgrus 0.2 m
1698301 | 24.2484 | Site - Asphalt - Asfaltbetong 0.03 m, A_Default_Building_Part 0.07 m, Site - Gravel - Stabilitet grus 0.2 m, Site - Gravel - Bunnsikringsgrus 0.2 m
1698301 | 3.76076 | Site - Asphalt - Asfaltbetong 0.03 m, A_Default_Building_Part 0.07 m, Site - Gravel - Stabilitet grus 0.2 m, Site - Gravel - Bunnsikringsgrus 0.2 m
1698301 | 4.16708 | Site - Asphalt - Asfaltbetong 0.03 m, A_Default_Building_Part 0.07 m, Site - Gravel - Stabilitet grus 0.2 m, Site - Gravel - Bunnsikringsgrus 0.2 m
1698301 | 2.94541 | Site - Asphalt - Asfaltbetong 0.03 m, A_Default_Building_Part 0.07 m, Site - Gravel - Stabilitet grus 0.2 m, Site - Gravel - Bunnsikringsgrus 0.2 m
1698301 | 3.04692 | Site - Asphalt - Asfaltbetong 0.03 m, A_Default_Building_Part 0.07 m, Site - Gravel - Stabilitet grus 0.2 m, Site - Gravel - Bunnsikringsgrus 0.2 m
1698301 | 3.20725 | Site - Asphalt - Asfaltbetong 0.03 m, A_Default_Building_Part 0.07 m, Site - Gravel - Stabilitet grus 0.2 m, Site - Gravel - Bunnsikringsgrus 0.2 m
1698301 | 3.77413 | Site - Asphalt - Asfaltbetong 0.03 m, A_Default_Building_Part 0.07 m, Site - Gravel - Stabilitet grus 0.2 m, Site - Gravel - Bunnsikringsgrus 0.2 m
1698301 | 3.87049 | Site - Asphalt - Asfaltbetong 0.03 m, A_Default_Building_Part 0.07 m, Site - Gravel - Stabilitet grus 0.2 m, Site - Gravel - Bunnsikringsgrus 0.2 m
1698301 | 3.21434 | Site - Asphalt - Asfaltbetong 0.03 m, A_Default_Building_Part 0.07 m, Site - Gravel - Stabilitet grus 0.2 m, Site - Gravel - Bunnsikringsgrus 0.2 m
1698301 | 3.13269 | Site - Asphalt - Asfaltbetong 0.03 m, A_Default_Building_Part 0.07 m, Site - Gravel - Stabilitet grus 0.2 m, Site - Gravel - Bunnsikringsgrus 0.2 m
1698301 | 3.13272 | Site - Asphalt - Asfaltbetong 0.03 m, A_Default_Building_Part 0.07 m, Site - Gravel - Stabilitet grus 0.2 m, Site - Gravel - Bunnsikringsgrus 0.2 m
1698301 | 4.12871 | Site - Asphalt - Asfaltbetong 0.03 m, A_Default_Building_Part 0.07 m, Site - Gravel - Stabilitet grus 0.2 m, Site - Gravel - Bunnsikringsgrus 0.2 m
1698301 | 5.11713 | Site - Asphalt - Asfaltbetong 0.03 m, A_Default_Building_Part 0.07 m, Site - Gravel - Stabilitet grus 0.2 m, Site - Gravel - Bunnsikringsgrus 0.2 m
1698301 | 5.64596 | Site - Asphalt - Asfaltbetong 0.03 m, A_Default_Building_Part 0.07 m, Site - Gravel - Stabilitet grus 0.2 m, Site - Gravel - Bunnsikringsgrus 0.2 m
1720829 | 1.89128
1720829 | 2.68764 | Site - Asphalt - Asfaltbetong 0.03 m, A_Default_Building_Part 0.07 m, Site - Gravel - Stabilitet grus 0.2 m, Site - Gravel - Bunnsikringsgrus 0.2 m
3 x 1720829 | 1.89128 | Site - Asphalt - Asfaltbetong 0.03 m, A_Default_Building_Part 0.07 m, Site - Gravel - Stabilitet grus 0.2 m, Site - Gravel - Bunnsikringsgrus 0.2 m
1720829 | 0.234101 | Site - Asphalt - Asfaltbetong 0.03 m, A_Default_Building_Part 0.07 m, Site - Gravel - Stabilitet grus 0.2 m, Site - Gravel - Bunnsikringsgrus 0.2 m
1720829 | 1.41042 | Site - Asphalt - Asfaltbetong 0.03 m, A_Default_Building_Part 0.07 m, Site - Gravel - Stabilitet grus 0.2 m, Site - Gravel - Bunnsikringsgrus 0.2 m
1720829 | 2.0368 | Site - Asphalt - Asfaltbetong 0.03 m, A_Default_Building_Part 0.07 m, Site - Gravel - Stabilitet grus 0.2 m, Site - Gravel - Bunnsikringsgrus 0.2 m
1720829 | 3.1171 | Site - Asphalt - Asfaltbetong 0.03 m, A_Default_Building_Part 0.07 m, Site - Gravel - Stabilitet grus 0.2 m, Site - Gravel - Bunnsikringsgrus 0.2 m
1720829 | 1.80505 | Site - Asphalt - Asfaltbetong 0.03 m, A_Default_Building_Part 0.07 m, Site - Gravel - Stabilitet grus 0.2 m, Site - Gravel - Bunnsikringsgrus 0.2 m
1720829 | 3.06235 | Site - Asphalt - Asfaltbetong 0.03 m, A_Default_Building_Part 0.07 m, Site - Gravel - Stabilitet grus 0.2 m, Site - Gravel - Bunnsikringsgrus 0.2 m
1720829 | 3.15304 | Site - Asphalt - Asfaltbetong 0.03 m, A_Default_Building_Part 0.07 m, Site - Gravel - Stabilitet grus 0.2 m, Site - Gravel - Bunnsikringsgrus 0.2 m
1720829 | 3.47037 | Site - Asphalt - Asfaltbetong 0.03 m, A_Default_Building_Part 0.07 m, Site - Gravel - Stabilitet grus 0.2 m, Site - Gravel - Bunnsikringsgrus 0.2 m
1720829 | 3.68917 | Site - Asphalt - Asfaltbetong 0.03 m, A_Default_Building_Part 0.07 m, Site - Gravel - Stabilitet grus 0.2 m, Site - Gravel - Bunnsikringsgrus 0.2 m
1720829 | 3.53416 | Site - Asphalt - Asfaltbetong 0.03 m, A_Default_Building_Part 0.07 m, Site - Gravel - Stabilitet grus 0.2 m, Site - Gravel - Bunnsikringsgrus 0.2 m
1720829 | 11.2125 | Site - Asphalt - Asfaltbetong 0.03 m, A_Default_Building_Part 0.07 m, Site - Gravel - Stabilitet grus 0.2 m, Site - Gravel - Bunnsikringsgrus 0.2 m
1720829 | 2.82776 | Site - Asphalt - Asfaltbetong 0.03 m, A_Default_Building_Part 0.07 m, Site - Gravel - Stabilitet grus 0.2 m, Site - Gravel - Bunnsikringsgrus 0.2 m
1720829 | 2.71652 | Site - Asphalt - Asfaltbetong 0.03 m, A_Default_Building_Part 0.07 m, Site - Gravel - Stabilitet grus 0.2 m, Site - Gravel - Bunnsikringsgrus 0.2 m
1720829 | 3.69578 | Site - Asphalt - Asfaltbetong 0.03 m, A_Default_Building_Part 0.07 m, Site - Gravel - Stabilitet grus 0.2 m, Site - Gravel - Bunnsikringsgrus 0.2 m
1720829 | 2.56872 | Site - Asphalt - Asfaltbetong 0.03 m, A_Default_Building_Part 0.07 m, Site - Gravel - Stabilitet grus 0.2 m, Site - Gravel - Bunnsikringsgrus 0.2 m
1720829 | 61.079 | Site - Asphalt - Asfaltbetong 0.03 m, A_Default_Building_Part 0.07 m, Site - Gravel - Stabilitet grus 0.2 m, Site - Gravel - Bunnsikringsgrus 0.2 m
1720829 | 11.3368 | Site - Asphalt - Asfaltbetong 0.03 m, A_Default_Building_Part 0.07 m, Site - Gravel - Stabilitet grus 0.2 m, Site - Gravel - Bunnsikringsgrus 0.2 m
1720829 | 0.460382 | Site - Asphalt - Asfaltbetong 0.03 m, A_Default_Building_Part 0.07 m, Site - Gravel - Stabilitet grus 0.2 m, Site - Gravel - Bunnsikringsgrus 0.2 m
1720829 | 0.526596 | Site - Asphalt - Asfaltbetong 0.03 m, A_Default_Building_Part 0.07 m, Site - Gravel - Stabilitet grus 0.2 m, Site - Gravel - Bunnsikringsgrus 0.2 m
1720829 | 0.520887 | Site - Asphalt - Asfaltbetong 0.03 m, A_Default_Building_Part 0.07 m, Site - Gravel - Stabilitet grus 0.2 m, Site - Gravel - Bunnsikringsgrus 0.2 m
1720829 | 0.78933 | Site - Asphalt - Asfaltbetong 0.03 m, A_Default_Building_Part 0.07 m, Site - Gravel - Stabilitet grus 0.2 m, Site - Gravel - Bunnsikringsgrus 0.2 m
1720829 | 1.60653 | Site - Asphalt - Asfaltbetong 0.03 m, A_Default_Building_Part 0.07 m, Site - Gravel - Stabilitet grus 0.2 m, Site - Gravel - Bunnsikringsgrus 0.2 m
1720829 | 2.19797 | Site - Asphalt - Asfaltbetong 0.03 m, A_Default_Building_Part 0.07 m, Site - Gravel - Stabilitet grus 0.2 m, Site - Gravel - Bunnsikringsgrus 0.2 m
1720829 | 2.26476 | Site - Asphalt - Asfaltbetong 0.03 m, A_Default_Building_Part 0.07 m, Site - Gravel - Stabilitet grus 0.2 m, Site - Gravel - Bunnsikringsgrus 0.2 m
1720829 | 3.10703 | Site - Asphalt - Asfaltbetong 0.03 m, A_Default_Building_Part 0.07 m, Site - Gravel - Stabilitet grus 0.2 m, Site - Gravel - Bunnsikringsgrus 0.2 m
1720829 | 7.16007 | Site - Asphalt - Asfaltbetong 0.03 m, A_Default_Building_Part 0.07 m, Site - Gravel - Stabilitet grus 0.2 m, Site - Gravel - Bunnsikringsgrus 0.2 m
1720829 | 2.3724 | Site - Asphalt - Asfaltbetong 0.03 m, A_Default_Building_Part 0.07 m, Site - Gravel - Stabilitet grus 0.2 m, Site - Gravel - Bunnsikringsgrus 0.2 m
1720829 | 5.16154 | Site - Asphalt - Asfaltbetong 0.03 m, A_Default_Building_Part 0.07 m, Site - Gravel - Stabilitet grus 0.2 m, Site - Gravel - Bunnsikringsgrus 0.2 m
1720829 | 2.04317 | Site - Asphalt - Asfaltbetong 0.03 m, A_Default_Building_Part 0.07 m, Site - Gravel - Stabilitet grus 0.2 m, Site - Gravel - Bunnsikringsgrus 0.2 m
1720829 | 2.93266 | Site - Asphalt - Asfaltbetong 0.03 m, A_Default_Building_Part 0.07 m, Site - Gravel - Stabilitet grus 0.2 m, Site - Gravel - Bunnsikringsgrus 0.2 m
1980344 | 6.9897
1980344 | 5.70788 | Site - Asphalt - Asfaltbetong 0.03 m, A_Default_Building_Part 0.07 m, Site - Gravel - Stabilitet grus 0.2 m, Site - Gravel - Bunnsikringsgrus 0.2 m
1980344 | 6.9897 | Site - Asphalt - Asfaltbetong 0.03 m, A_Default_Building_Part 0.07 m, Site - Gravel - Stabilitet grus 0.2 m, Site - Gravel - Bunnsikringsgrus 0.2 m
1980344 | 6.11027 | Site - Asphalt - Asfaltbetong 0.03 m, A_Default_Building_Part 0.07 m, Site - Gravel - Stabilitet grus 0.2 m, Site - Gravel - Bunnsikringsgrus 0.2 m
1980344 | 13.7633 | Site - Asphalt - Asfaltbetong 0.03 m, A_Default_Building_Part 0.07 m, Site - Gravel - Stabilitet grus 0.2 m, Site - Gravel - Bunnsikringsgrus 0.2 m

# IfcSlab: Floor:761 Asfalt - Kjørearealer, Floor:761 Asfalt - Kjørearealer:1953627
In: 00 - HAV
Type - PredefinedType: FLOOR; Material: Site - Asphalt - Asfaltbetong 0.03 m, A_Default_Building_Part 0.07 m, Site - Gravel - Stabilitet grus 0.2 m, Site - Gravel - Bunnsikringsgrus 0.2 m
Classification: 761 Veger (Uniformat)
Pset_QuantityTakeOff - Reference: 761 Asfalt - Kjørearealer; sets with these values: 2
Pset_SlabCommon - IsExternal: yes; LoadBearing: no; Reference: 761 Asfalt - Kjørearealer; PitchAngle: 0 deg

# IfcSlab: Floor:761 Betongbelegg - Gangarealer (5)
In: 00 - HAV
Classification: 761 Veger (Uniformat)
Pset_QuantityTakeOff - Reference: 761 Betongbelegg - Gangarealer; sets with these values: 2
Pset_SlabCommon - IsExternal: yes; LoadBearing: no; Reference: 761 Betongbelegg - Gangarealer
Name (Floor:761 Betongbelegg - Gangarealer:...) | PitchAngle (deg) | Material
1702303 | 2.6607
1702303 | 4.65072 | Site - Concrete - Betongbelegg 0.08 m, Site - Sand - Afretningssand 0.03 m, Site - Gravel - Stabilitet grus 0.15 m, Site - Gravel - Bunnsikringsgrus 0.15 m
2 x 1702303 | 2.6607 | Site - Concrete - Betongbelegg 0.08 m, Site - Sand - Afretningssand 0.03 m, Site - Gravel - Stabilitet grus 0.15 m, Site - Gravel - Bunnsikringsgrus 0.15 m
1702303 | 3.24623 | Site - Concrete - Betongbelegg 0.08 m, Site - Sand - Afretningssand 0.03 m, Site - Gravel - Stabilitet grus 0.15 m, Site - Gravel - Bunnsikringsgrus 0.15 m

# IfcSlab: Floor:761 Betongbelegg - Gangarealer (3)
In: 00 - HAV
Type - PredefinedType: FLOOR; Material: Site - Concrete - Betongbelegg 0.08 m, Site - Sand - Afretningssand 0.03 m, Site - Gravel - Stabilitet grus 0.15 m, Site - Gravel - Bunnsikringsgrus 0.15 m
Classification: 761 Veger (Uniformat)
Pset_QuantityTakeOff - Reference: 761 Betongbelegg - Gangarealer; sets with these values: 2
Pset_SlabCommon - IsExternal: yes; LoadBearing: no; Reference: 761 Betongbelegg - Gangarealer
Name (Floor:761 Betongbelegg - Gangarealer:...) | PitchAngle (deg)
1701355 | 0
1730186 | 0
1731386 | 1.9287 | Material: Site - Concrete - Betongbelegg, Site - Sand - Afretningssand, Site - Gravel - Stabilitet grus, Site - Gravel - Bunnsikringsgrus

# IfcSlab: Floor:761 grus - Gangarealer, Floor:761 grus - Gangarealer:1950364
In: 00 - HAV
Type - PredefinedType: FLOOR; Material: Site - Gravel - Stabilitet grus 0.08 m, Site - Sand - Afretningssand 0.03 m, Site - Gravel - Stabilitet grus 0.15 m, Site - Gravel - Bunnsikringsgrus 0.15 m
Classification: 761 Veger (Uniformat)
Pset_QuantityTakeOff - Reference: 761 grus - Gangarealer; sets with these values: 2
Pset_SlabCommon - IsExternal: yes; LoadBearing: no; PitchAngle: 0 deg; Reference: 761 grus - Gangarealer

# IfcSlab: Floor:771 Grøntarealer (165)
In: 00 - HAV
Classification: 771 Gressarealer (Uniformat)
Pset_QuantityTakeOff - Reference: 771 Grøntarealer; sets with these values: 2
Pset_SlabCommon - Reference: 771 Grøntarealer; IsExternal: yes; LoadBearing: no
Name (Floor:771 Grøntarealer:...) | PitchAngle (deg) | Material
1694113 | 20.9466
1694113 | 7.26176 | 815 - Terrain, Grøntareal 0.02 m, Site - Soil - Jordlag 0.3 m
1694113 | 5.49107 | 815 - Terrain, Grøntareal 0.02 m, Site - Soil - Jordlag 0.3 m
1694113 | 12.631 | 815 - Terrain, Grøntareal 0.02 m, Site - Soil - Jordlag 0.3 m
1694113 | 12.6347 | 815 - Terrain, Grøntareal 0.02 m, Site - Soil - Jordlag 0.3 m
3 x 1694113 | 20.9466 | 815 - Terrain, Grøntareal 0.02 m, Site - Soil - Jordlag 0.3 m
1694113 | 12.4089 | 815 - Terrain, Grøntareal 0.02 m, Site - Soil - Jordlag 0.3 m
1694113 | 11.4206 | 815 - Terrain, Grøntareal 0.02 m, Site - Soil - Jordlag 0.3 m
1694113 | 11.3333 | 815 - Terrain, Grøntareal 0.02 m, Site - Soil - Jordlag 0.3 m
1694113 | 10.755 | 815 - Terrain, Grøntareal 0.02 m, Site - Soil - Jordlag 0.3 m
1694113 | 11.1385 | 815 - Terrain, Grøntareal 0.02 m, Site - Soil - Jordlag 0.3 m
1694113 | 9.97914 | 815 - Terrain, Grøntareal 0.02 m, Site - Soil - Jordlag 0.3 m
1694113 | 15.7449 | 815 - Terrain, Grøntareal 0.02 m, Site - Soil - Jordlag 0.3 m
1694113 | 13.5618 | 815 - Terrain, Grøntareal 0.02 m, Site - Soil - Jordlag 0.3 m
1694113 | 8.78462 | 815 - Terrain, Grøntareal 0.02 m, Site - Soil - Jordlag 0.3 m
1694113 | 16.4317 | 815 - Terrain, Grøntareal 0.02 m, Site - Soil - Jordlag 0.3 m
1694113 | 15.9937 | 815 - Terrain, Grøntareal 0.02 m, Site - Soil - Jordlag 0.3 m
1694113 | 6.2286 | 815 - Terrain, Grøntareal 0.02 m, Site - Soil - Jordlag 0.3 m
1694113 | 7.25793 | 815 - Terrain, Grøntareal 0.02 m, Site - Soil - Jordlag 0.3 m
1694113 | 3.94836 | 815 - Terrain, Grøntareal 0.02 m, Site - Soil - Jordlag 0.3 m
1694113 | 5.34536 | 815 - Terrain, Grøntareal 0.02 m, Site - Soil - Jordlag 0.3 m
1694113 | 2.77577 | 815 - Terrain, Grøntareal 0.02 m, Site - Soil - Jordlag 0.3 m
1694113 | 2.84629 | 815 - Terrain, Grøntareal 0.02 m, Site - Soil - Jordlag 0.3 m
1694113 | 3.49592 | 815 - Terrain, Grøntareal 0.02 m, Site - Soil - Jordlag 0.3 m
1694113 | 5.31923 | 815 - Terrain, Grøntareal 0.02 m, Site - Soil - Jordlag 0.3 m
1694113 | 6.51481 | 815 - Terrain, Grøntareal 0.02 m, Site - Soil - Jordlag 0.3 m
1694113 | 2.1116 | 815 - Terrain, Grøntareal 0.02 m, Site - Soil - Jordlag 0.3 m
1694113 | 0.976441 | 815 - Terrain, Grøntareal 0.02 m, Site - Soil - Jordlag 0.3 m
1694113 | 2.2188 | 815 - Terrain, Grøntareal 0.02 m, Site - Soil - Jordlag 0.3 m
1694113 | 2.61325 | 815 - Terrain, Grøntareal 0.02 m, Site - Soil - Jordlag 0.3 m
1694113 | 8.79146 | 815 - Terrain, Grøntareal 0.02 m, Site - Soil - Jordlag 0.3 m
1694113 | 2.10861 | 815 - Terrain, Grøntareal 0.02 m, Site - Soil - Jordlag 0.3 m
1694113 | 4.83916 | 815 - Terrain, Grøntareal 0.02 m, Site - Soil - Jordlag 0.3 m
1694113 | 2.33456 | 815 - Terrain, Grøntareal 0.02 m, Site - Soil - Jordlag 0.3 m
1694113 | 0.508893 | 815 - Terrain, Grøntareal 0.02 m, Site - Soil - Jordlag 0.3 m
1694113 | 15.9158 | 815 - Terrain, Grøntareal 0.02 m, Site - Soil - Jordlag 0.3 m
1694113 | 5.46606 | 815 - Terrain, Grøntareal 0.02 m, Site - Soil - Jordlag 0.3 m
1694113 | 14.56 | 815 - Terrain, Grøntareal 0.02 m, Site - Soil - Jordlag 0.3 m
1694113 | 7.77941 | 815 - Terrain, Grøntareal 0.02 m, Site - Soil - Jordlag 0.3 m
1694113 | 4.52001 | 815 - Terrain, Grøntareal 0.02 m, Site - Soil - Jordlag 0.3 m
1694113 | 22.3035 | 815 - Terrain, Grøntareal 0.02 m, Site - Soil - Jordlag 0.3 m
1694113 | 27.0457 | 815 - Terrain, Grøntareal 0.02 m, Site - Soil - Jordlag 0.3 m
1696619 | 3.52116
1696619 | 4.0234 | 815 - Terrain, Grøntareal 0.02 m, Site - Soil - Jordlag 0.3 m
1696619 | 5.07179 | 815 - Terrain, Grøntareal 0.02 m, Site - Soil - Jordlag 0.3 m
1696619 | 4.87948 | 815 - Terrain, Grøntareal 0.02 m, Site - Soil - Jordlag 0.3 m
1696619 | 5.44669 | 815 - Terrain, Grøntareal 0.02 m, Site - Soil - Jordlag 0.3 m
1696619 | 6.28501 | 815 - Terrain, Grøntareal 0.02 m, Site - Soil - Jordlag 0.3 m
1696619 | 4.8984 | 815 - Terrain, Grøntareal 0.02 m, Site - Soil - Jordlag 0.3 m
1696619 | 5.2218 | 815 - Terrain, Grøntareal 0.02 m, Site - Soil - Jordlag 0.3 m
1696619 | 5.27106 | 815 - Terrain, Grøntareal 0.02 m, Site - Soil - Jordlag 0.3 m
1696619 | 5.0775 | 815 - Terrain, Grøntareal 0.02 m, Site - Soil - Jordlag 0.3 m
1696619 | 5.17859 | 815 - Terrain, Grøntareal 0.02 m, Site - Soil - Jordlag 0.3 m
1696619 | 5.2846 | 815 - Terrain, Grøntareal 0.02 m, Site - Soil - Jordlag 0.3 m
1696619 | 8.59197 | 815 - Terrain, Grøntareal 0.02 m, Site - Soil - Jordlag 0.3 m
1696619 | 6.88061 | 815 - Terrain, Grøntareal 0.02 m, Site - Soil - Jordlag 0.3 m
1696619 | 6.90013 | 815 - Terrain, Grøntareal 0.02 m, Site - Soil - Jordlag 0.3 m
1696619 | 7.2727 | 815 - Terrain, Grøntareal 0.02 m, Site - Soil - Jordlag 0.3 m
1696619 | 7.21352 | 815 - Terrain, Grøntareal 0.02 m, Site - Soil - Jordlag 0.3 m
1696619 | 5.8539 | 815 - Terrain, Grøntareal 0.02 m, Site - Soil - Jordlag 0.3 m
1696619 | 6.09261 | 815 - Terrain, Grøntareal 0.02 m, Site - Soil - Jordlag 0.3 m
1696619 | 5.10638 | 815 - Terrain, Grøntareal 0.02 m, Site - Soil - Jordlag 0.3 m
1696619 | 5.2855 | 815 - Terrain, Grøntareal 0.02 m, Site - Soil - Jordlag 0.3 m
1696619 | 6.46076 | 815 - Terrain, Grøntareal 0.02 m, Site - Soil - Jordlag 0.3 m
1696619 | 5.92534 | 815 - Terrain, Grøntareal 0.02 m, Site - Soil - Jordlag 0.3 m
1696619 | 5.92873 | 815 - Terrain, Grøntareal 0.02 m, Site - Soil - Jordlag 0.3 m
1696619 | 4.24376 | 815 - Terrain, Grøntareal 0.02 m, Site - Soil - Jordlag 0.3 m
1696619 | 3.91801 | 815 - Terrain, Grøntareal 0.02 m, Site - Soil - Jordlag 0.3 m
1696619 | 2.87914 | 815 - Terrain, Grøntareal 0.02 m, Site - Soil - Jordlag 0.3 m
1696619 | 3.10586 | 815 - Terrain, Grøntareal 0.02 m, Site - Soil - Jordlag 0.3 m
1696619 | 4.34904 | 815 - Terrain, Grøntareal 0.02 m, Site - Soil - Jordlag 0.3 m
1696619 | 4.05348 | 815 - Terrain, Grøntareal 0.02 m, Site - Soil - Jordlag 0.3 m
1696619 | 3.08879 | 815 - Terrain, Grøntareal 0.02 m, Site - Soil - Jordlag 0.3 m
1696619 | 4.62321 | 815 - Terrain, Grøntareal 0.02 m, Site - Soil - Jordlag 0.3 m
1696619 | 2.79386 | 815 - Terrain, Grøntareal 0.02 m, Site - Soil - Jordlag 0.3 m
1696619 | 2.7778 | 815 - Terrain, Grøntareal 0.02 m, Site - Soil - Jordlag 0.3 m
1696619 | 3.06622 | 815 - Terrain, Grøntareal 0.02 m, Site - Soil - Jordlag 0.3 m
1696619 | 2.65337 | 815 - Terrain, Grøntareal 0.02 m, Site - Soil - Jordlag 0.3 m
1696619 | 2.52076 | 815 - Terrain, Grøntareal 0.02 m, Site - Soil - Jordlag 0.3 m
1696619 | 0.482267 | 815 - Terrain, Grøntareal 0.02 m, Site - Soil - Jordlag 0.3 m
1696619 | 1.97608 | 815 - Terrain, Grøntareal 0.02 m, Site - Soil - Jordlag 0.3 m
1696619 | 2.25314 | 815 - Terrain, Grøntareal 0.02 m, Site - Soil - Jordlag 0.3 m
1696619 | 7.24129 | 815 - Terrain, Grøntareal 0.02 m, Site - Soil - Jordlag 0.3 m
1696619 | 1.76147 | 815 - Terrain, Grøntareal 0.02 m, Site - Soil - Jordlag 0.3 m
1696619 | 3.28503 | 815 - Terrain, Grøntareal 0.02 m, Site - Soil - Jordlag 0.3 m
1696619 | 7.19496 | 815 - Terrain, Grøntareal 0.02 m, Site - Soil - Jordlag 0.3 m
1696619 | 4.89648 | 815 - Terrain, Grøntareal 0.02 m, Site - Soil - Jordlag 0.3 m
1696619 | 4.26204 | 815 - Terrain, Grøntareal 0.02 m, Site - Soil - Jordlag 0.3 m
1696619 | 3.72426 | 815 - Terrain, Grøntareal 0.02 m, Site - Soil - Jordlag 0.3 m
1696619 | 3.52116 | 815 - Terrain, Grøntareal 0.02 m, Site - Soil - Jordlag 0.3 m
1696619 | 3.1225 | 815 - Terrain, Grøntareal 0.02 m, Site - Soil - Jordlag 0.3 m
1696619 | 2.80873 | 815 - Terrain, Grøntareal 0.02 m, Site - Soil - Jordlag 0.3 m
1696619 | 3.16946 | 815 - Terrain, Grøntareal 0.02 m, Site - Soil - Jordlag 0.3 m
1696619 | 1.99324 | 815 - Terrain, Grøntareal 0.02 m, Site - Soil - Jordlag 0.3 m
1696619 | 8.69048 | 815 - Terrain, Grøntareal 0.02 m, Site - Soil - Jordlag 0.3 m
1696619 | 3.90917 | 815 - Terrain, Grøntareal 0.02 m, Site - Soil - Jordlag 0.3 m
1696619 | 5.42131 | 815 - Terrain, Grøntareal 0.02 m, Site - Soil - Jordlag 0.3 m
1696619 | 3.51129 | 815 - Terrain, Grøntareal 0.02 m, Site - Soil - Jordlag 0.3 m
1696619 | 3.28819 | 815 - Terrain, Grøntareal 0.02 m, Site - Soil - Jordlag 0.3 m
1697511 | 12.393
1697511 | 0.246702 | 815 - Terrain, Grøntareal 0.02 m, Site - Soil - Jordlag 0.3 m
1697511 | 12.4682 | 815 - Terrain, Grøntareal 0.02 m, Site - Soil - Jordlag 0.3 m
1697511 | 5.50871 | 815 - Terrain, Grøntareal 0.02 m, Site - Soil - Jordlag 0.3 m
1697511 | 2.58491 | 815 - Terrain, Grøntareal 0.02 m, Site - Soil - Jordlag 0.3 m
1697511 | 6.95326 | 815 - Terrain, Grøntareal 0.02 m, Site - Soil - Jordlag 0.3 m
1697511 | 9.94914 | 815 - Terrain, Grøntareal 0.02 m, Site - Soil - Jordlag 0.3 m
1697511 | 86.943 | 815 - Terrain, Grøntareal 0.02 m, Site - Soil - Jordlag 0.3 m
1697511 | 87.6172 | 815 - Terrain, Grøntareal 0.02 m, Site - Soil - Jordlag 0.3 m
1697511 | 59.4671 | 815 - Terrain, Grøntareal 0.02 m, Site - Soil - Jordlag 0.3 m
1697511 | 8.71214 | 815 - Terrain, Grøntareal 0.02 m, Site - Soil - Jordlag 0.3 m
1697511 | 22.4849 | 815 - Terrain, Grøntareal 0.02 m, Site - Soil - Jordlag 0.3 m
1697511 | 7.70643 | 815 - Terrain, Grøntareal 0.02 m, Site - Soil - Jordlag 0.3 m
1697511 | 7.26183 | 815 - Terrain, Grøntareal 0.02 m, Site - Soil - Jordlag 0.3 m
1697511 | 18.6182 | 815 - Terrain, Grøntareal 0.02 m, Site - Soil - Jordlag 0.3 m
1697511 | 31.5007 | 815 - Terrain, Grøntareal 0.02 m, Site - Soil - Jordlag 0.3 m
1697511 | 31.4532 | 815 - Terrain, Grøntareal 0.02 m, Site - Soil - Jordlag 0.3 m
1697511 | 16.0551 | 815 - Terrain, Grøntareal 0.02 m, Site - Soil - Jordlag 0.3 m
1697511 | 22.1037 | 815 - Terrain, Grøntareal 0.02 m, Site - Soil - Jordlag 0.3 m
1697511 | 22.0807 | 815 - Terrain, Grøntareal 0.02 m, Site - Soil - Jordlag 0.3 m
1697511 | 5.20259 | 815 - Terrain, Grøntareal 0.02 m, Site - Soil - Jordlag 0.3 m
1697511 | 12.393 | 815 - Terrain, Grøntareal 0.02 m, Site - Soil - Jordlag 0.3 m
1697511 | 7.82226 | 815 - Terrain, Grøntareal 0.02 m, Site - Soil - Jordlag 0.3 m
1697511 | 3.04752 | 815 - Terrain, Grøntareal 0.02 m, Site - Soil - Jordlag 0.3 m
1697511 | 4.58194 | 815 - Terrain, Grøntareal 0.02 m, Site - Soil - Jordlag 0.3 m
1697511 | 14.4845 | 815 - Terrain, Grøntareal 0.02 m, Site - Soil - Jordlag 0.3 m
1697511 | 32.732 | 815 - Terrain, Grøntareal 0.02 m, Site - Soil - Jordlag 0.3 m
1697511 | 5.59735 | 815 - Terrain, Grøntareal 0.02 m, Site - Soil - Jordlag 0.3 m
1697511 | 2.81607 | 815 - Terrain, Grøntareal 0.02 m, Site - Soil - Jordlag 0.3 m
1697511 | 6.29305 | 815 - Terrain, Grøntareal 0.02 m, Site - Soil - Jordlag 0.3 m
1697511 | 3.92675 | 815 - Terrain, Grøntareal 0.02 m, Site - Soil - Jordlag 0.3 m
1697511 | 8.89463 | 815 - Terrain, Grøntareal 0.02 m, Site - Soil - Jordlag 0.3 m
1697511 | 3.45383 | 815 - Terrain, Grøntareal 0.02 m, Site - Soil - Jordlag 0.3 m
1697511 | 7.6652 | 815 - Terrain, Grøntareal 0.02 m, Site - Soil - Jordlag 0.3 m
1697511 | 19.4288 | 815 - Terrain, Grøntareal 0.02 m, Site - Soil - Jordlag 0.3 m
1697511 | 19.09 | 815 - Terrain, Grøntareal 0.02 m, Site - Soil - Jordlag 0.3 m
1697511 | 29.2274 | 815 - Terrain, Grøntareal 0.02 m, Site - Soil - Jordlag 0.3 m
1697511 | 27.8549 | 815 - Terrain, Grøntareal 0.02 m, Site - Soil - Jordlag 0.3 m
1697511 | 31.1216 | 815 - Terrain, Grøntareal 0.02 m, Site - Soil - Jordlag 0.3 m
1697511 | 24.178 | 815 - Terrain, Grøntareal 0.02 m, Site - Soil - Jordlag 0.3 m
1697511 | 29.9295 | 815 - Terrain, Grøntareal 0.02 m, Site - Soil - Jordlag 0.3 m
1697511 | 37.2663 | 815 - Terrain, Grøntareal 0.02 m, Site - Soil - Jordlag 0.3 m
1697511 | 19.5068 | 815 - Terrain, Grøntareal 0.02 m, Site - Soil - Jordlag 0.3 m
1697511 | 0.630857 | 815 - Terrain, Grøntareal 0.02 m, Site - Soil - Jordlag 0.3 m
1697511 | 48.7063 | 815 - Terrain, Grøntareal 0.02 m, Site - Soil - Jordlag 0.3 m
1697511 | 34.2858 | 815 - Terrain, Grøntareal 0.02 m, Site - Soil - Jordlag 0.3 m
1697511 | 37.7511 | 815 - Terrain, Grøntareal 0.02 m, Site - Soil - Jordlag 0.3 m
1697511 | 41.6941 | 815 - Terrain, Grøntareal 0.02 m, Site - Soil - Jordlag 0.3 m
1697511 | 36.4966 | 815 - Terrain, Grøntareal 0.02 m, Site - Soil - Jordlag 0.3 m
1697511 | 33.2883 | 815 - Terrain, Grøntareal 0.02 m, Site - Soil - Jordlag 0.3 m
1697511 | 25.0661 | 815 - Terrain, Grøntareal 0.02 m, Site - Soil - Jordlag 0.3 m
1697511 | 34.0072 | 815 - Terrain, Grøntareal 0.02 m, Site - Soil - Jordlag 0.3 m
1697511 | 30.3489 | 815 - Terrain, Grøntareal 0.02 m, Site - Soil - Jordlag 0.3 m
1697511 | 29.8455 | 815 - Terrain, Grøntareal 0.02 m, Site - Soil - Jordlag 0.3 m
1697511 | 38.9282 | 815 - Terrain, Grøntareal 0.02 m, Site - Soil - Jordlag 0.3 m
1697511 | 34.0199 | 815 - Terrain, Grøntareal 0.02 m, Site - Soil - Jordlag 0.3 m
1697511 | 51.5517 | 815 - Terrain, Grøntareal 0.02 m, Site - Soil - Jordlag 0.3 m
1697511 | 52.0489 | 815 - Terrain, Grøntareal 0.02 m, Site - Soil - Jordlag 0.3 m
1697511 | 29.3001 | 815 - Terrain, Grøntareal 0.02 m, Site - Soil - Jordlag 0.3 m
1697511 | 30.1901 | 815 - Terrain, Grøntareal 0.02 m, Site - Soil - Jordlag 0.3 m
1697511 | 30.0793 | 815 - Terrain, Grøntareal 0.02 m, Site - Soil - Jordlag 0.3 m
1697511 | 25.785 | 815 - Terrain, Grøntareal 0.02 m, Site - Soil - Jordlag 0.3 m
1697511 | 30.4733 | 815 - Terrain, Grøntareal 0.02 m, Site - Soil - Jordlag 0.3 m
1697511 | 29.5565 | 815 - Terrain, Grøntareal 0.02 m, Site - Soil - Jordlag 0.3 m

# IfcSlab: Floor:771 Grøntarealer, Floor:771 Grøntarealer:1707359
In: 00 - HAV
Type - PredefinedType: FLOOR
Classification: 771 Gressarealer (Uniformat); Material: 815 - Terrain, Grøntareal, Site - Soil - Jordlag
Pset_QuantityTakeOff - Reference: 771 Grøntarealer; sets with these values: 2
Pset_SlabCommon - Reference: 771 Grøntarealer; IsExternal: yes; LoadBearing: no; PitchAngle: 23.766 deg

# IfcSlab: Floor:771 Grøntarealer 2 (17)
In: 00 - HAV
Classification: 771 Gressarealer (Uniformat)
Pset_QuantityTakeOff - Reference: 771 Grøntarealer 2; sets with these values: 2
Pset_SlabCommon - IsExternal: yes; LoadBearing: no; Reference: 771 Grøntarealer 2
Name (Floor:771 Grøntarealer 2:...) | PitchAngle (deg) | Material
1700201 | 13.9134
1700201 | 15.8169 | 815 - Terrain, Grøntareal 0.02 m, Site - Soil - Jordlag 0.3 m
1700201 | 23.7623 | 815 - Terrain, Grøntareal 0.02 m, Site - Soil - Jordlag 0.3 m
1700201 | 23.7898 | 815 - Terrain, Grøntareal 0.02 m, Site - Soil - Jordlag 0.3 m
1700201 | 13.9134 | 815 - Terrain, Grøntareal 0.02 m, Site - Soil - Jordlag 0.3 m
1700201 | 4.5267 | 815 - Terrain, Grøntareal 0.02 m, Site - Soil - Jordlag 0.3 m
1772613 | 26.6671
1772613 | 24.6491 | 815 - Terrain, Grøntareal 0.02 m, Site - Soil - Jordlag 0.3 m
1772613 | 77.6098 | 815 - Terrain, Grøntareal 0.02 m, Site - Soil - Jordlag 0.3 m
1772613 | 26.6671 | 815 - Terrain, Grøntareal 0.02 m, Site - Soil - Jordlag 0.3 m
1772613 | 27.8295 | 815 - Terrain, Grøntareal 0.02 m, Site - Soil - Jordlag 0.3 m
1772613 | 27.9053 | 815 - Terrain, Grøntareal 0.02 m, Site - Soil - Jordlag 0.3 m
1772613 | 27.9009 | 815 - Terrain, Grøntareal 0.02 m, Site - Soil - Jordlag 0.3 m
1772613 | 27.9013 | 815 - Terrain, Grøntareal 0.02 m, Site - Soil - Jordlag 0.3 m
1772613 | 28.6272 | 815 - Terrain, Grøntareal 0.02 m, Site - Soil - Jordlag 0.3 m
1772613 | 80.865 | 815 - Terrain, Grøntareal 0.02 m, Site - Soil - Jordlag 0.3 m
1772613 | 24.4647 | 815 - Terrain, Grøntareal 0.02 m, Site - Soil - Jordlag 0.3 m

# IfcSlab: Floor:771 Grøntarealer 2 (2)
In: 00 - HAV
Type - PredefinedType: FLOOR
Classification: 771 Gressarealer (Uniformat); Material: 815 - Terrain, Grøntareal, Site - Soil - Jordlag
Pset_QuantityTakeOff - Reference: 771 Grøntarealer 2; sets with these values: 2
Pset_SlabCommon - IsExternal: yes; LoadBearing: no; Reference: 771 Grøntarealer 2
Name (Floor:771 Grøntarealer 2:...) | PitchAngle (deg)
1697252 | 3.42931
1980210 | 6.9625

# IfcSlab: Pad:710 Sand (Bearbeidet terreng), 150mm, Pad:710 Sand (Bearbeidet terreng), 150mm:1749298
In: 00 - HAV
Type - PredefinedType: FLOOR; Material: A_Default_Building_Component 0.15 m
Classification: 71 Bearbeidet terreng (Uniformat)
Pset_QuantityTakeOff - Reference: 710 Sand (Bearbeidet terreng), 150mm; sets with these values: 2
Pset_SlabCommon - PitchAngle: 0 deg; Reference: 710 Sand (Bearbeidet terreng), 150mm; IsExternal: no

# IfcStair: Cast-In-Place Stair:Cast-In-Place Stair, Cast-In-Place Stair:Stair:1729662
In: 00 - HAV
ShapeType: STRAIGHT_RUN_STAIR
Pset_QuantityTakeOff - Reference: Cast-In-Place Stair
Pset_StairCommon - IsExternal: yes; Reference: Cast-In-Place Stair; NumberOfRiser: 10; NumberOfTreads: 9; RiserHeight: 0.179294 m; TreadLength: 0.28 m

# IfcStair: Cast-In-Place Stair:Utetrapp - betong, Cast-In-Place Stair:Stair:1703353
In: 00 - HAV
ShapeType: STRAIGHT_RUN_STAIR
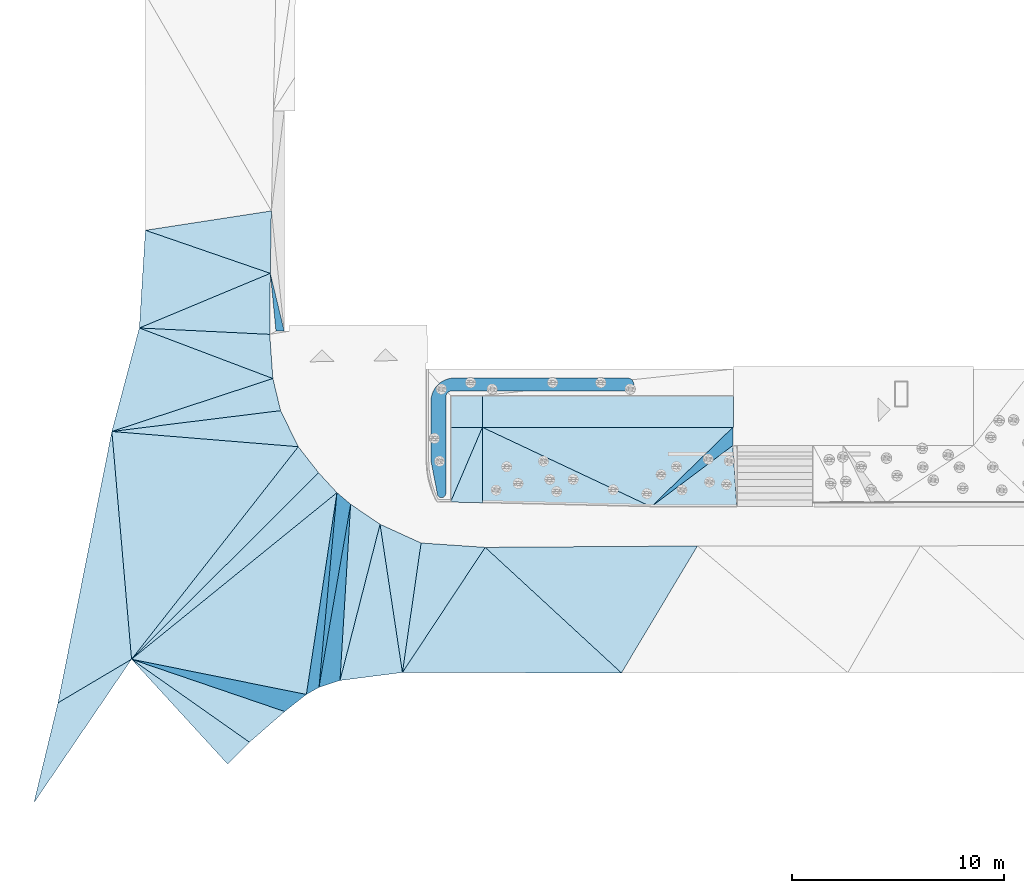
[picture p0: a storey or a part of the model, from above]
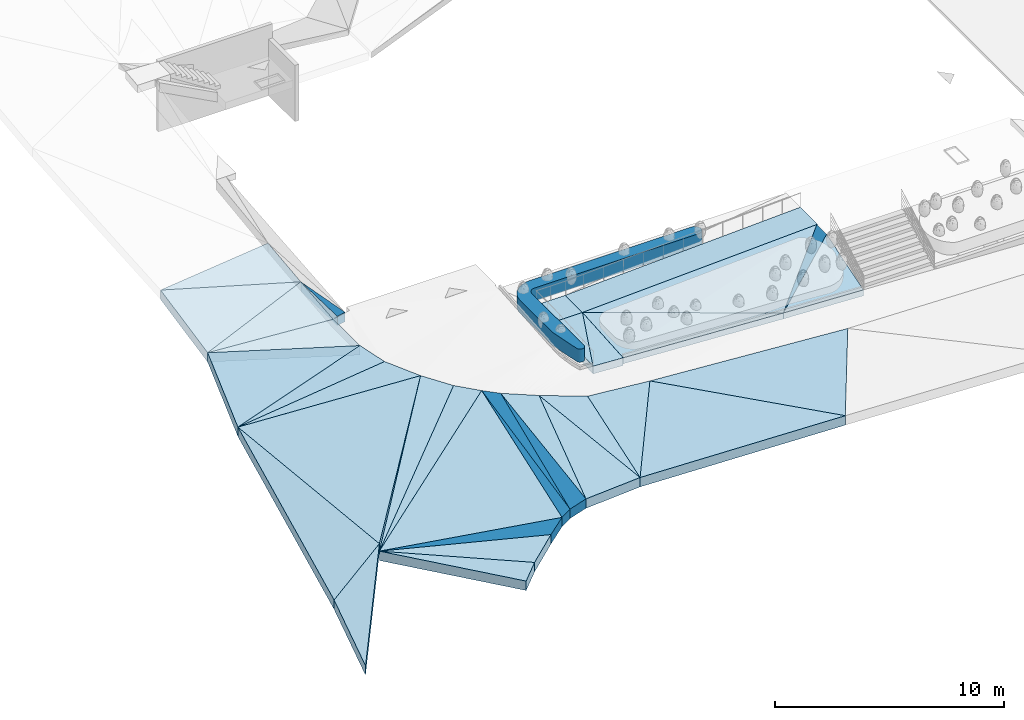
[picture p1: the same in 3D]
Properties of the parts of a building model (IFC2X3), part 2 of 2

# IfcStair: Cast-In-Place Stair:Utetrapp - betong, Cast-In-Place Stair:Stair:1703353
Pset_QuantityTakeOff - Reference: Utetrapp - betong
Pset_StairCommon - IsExternal: yes; Reference: Utetrapp - betong; NumberOfRiser: 10; NumberOfTreads: 9; RiserHeight: 0.179294 m; TreadLength: 0.32 m

# IfcStairFlight: Monolithic Run:Monolithic Run, Cast-In-Place Stair:Stair:1729662 Run 1
In: 00 - HAV
Type - PredefinedType: STRAIGHT
Type - Pset_StairFlightCommon - NosingLength: 0 m
NumberOfRiser: 10; NumberOfTreads: 9; RiserHeight: 0.588235 m; TreadLength: 0.918635 m; Material: A_Default_Building_Part
Pset_QuantityTakeOff - Reference: Monolithic Run
Pset_StairFlightCommon - Reference: Monolithic Run; NumberOfRiser: 10; NumberOfTreads: 9; RiserHeight: 0.179294 m; TreadLength: 0.28 m; WalkingLineOffset: 1.75033 m; TreadLengthAtOffset: 0.28 m; TreadLengthAtInnerSide: 0.28 m

# IfcStairFlight: Monolithic Run:Monolittisk, Cast-In-Place Stair:Stair:1703353 Run 1
In: 00 - HAV
Type - PredefinedType: STRAIGHT
Type - Pset_StairFlightCommon - NosingLength: 0 m
NumberOfRiser: 10; NumberOfTreads: 9; RiserHeight: 0.588235 m; TreadLength: 1.04987 m; Material: A_Finish_Metal_Steel_Brushed, Focus - Betong
Pset_QuantityTakeOff - Reference: Monolittisk
Pset_StairFlightCommon - Reference: Monolittisk; NumberOfRiser: 10; NumberOfTreads: 9; RiserHeight: 0.179294 m; TreadLength: 0.32 m; WalkingLineOffset: 5.90551 m; TreadLengthAtOffset: 0.32 m; TreadLengthAtInnerSide: 0.32 m

# IfcWallStandardCase: Basic Wall:721 Støttemur 200mm (3)
In: 00 - HAV
Type - PredefinedType: STANDARD; Material: A_Default_Building_Part 0.2 m
Classification: 721 Støttemurer og andre murer (Uniformat)
Pset_QuantityTakeOff - Reference: 721 Støttemur 200mm; sets with these values: 2
Pset_WallCommon - IsExternal: yes; LoadBearing: no; ExtendToStructure: no; Reference: 721 Støttemur 200mm
Name (Basic Wall:721 Støttemur 200mm:...)
1765856
1978899
1978903

# IfcWallStandardCase: Basic Wall:721 Støttemur eksisterende 300mm (2)
In: 00 - HAV
Type - PredefinedType: STANDARD; Material: Støttemur eksisterende rød 0.2 m
Classification: 721 Støttemurer og andre murer (Uniformat)
Pset_QuantityTakeOff - Reference: 721 Støttemur eksisterende 300mm; sets with these values: 2
Pset_WallCommon - IsExternal: yes; LoadBearing: no; Reference: 721 Støttemur eksisterende 300mm; ExtendToStructure: no
Name (Basic Wall:721 Støttemur eksisterende 300mm:...)
1717991
1718355
